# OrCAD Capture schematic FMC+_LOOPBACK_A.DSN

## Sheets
1 Title, Note, Block Diagram: title: FMC+ Loopback Card; rev: A1; note: 150-0330631-A1       (6XX-44455R)
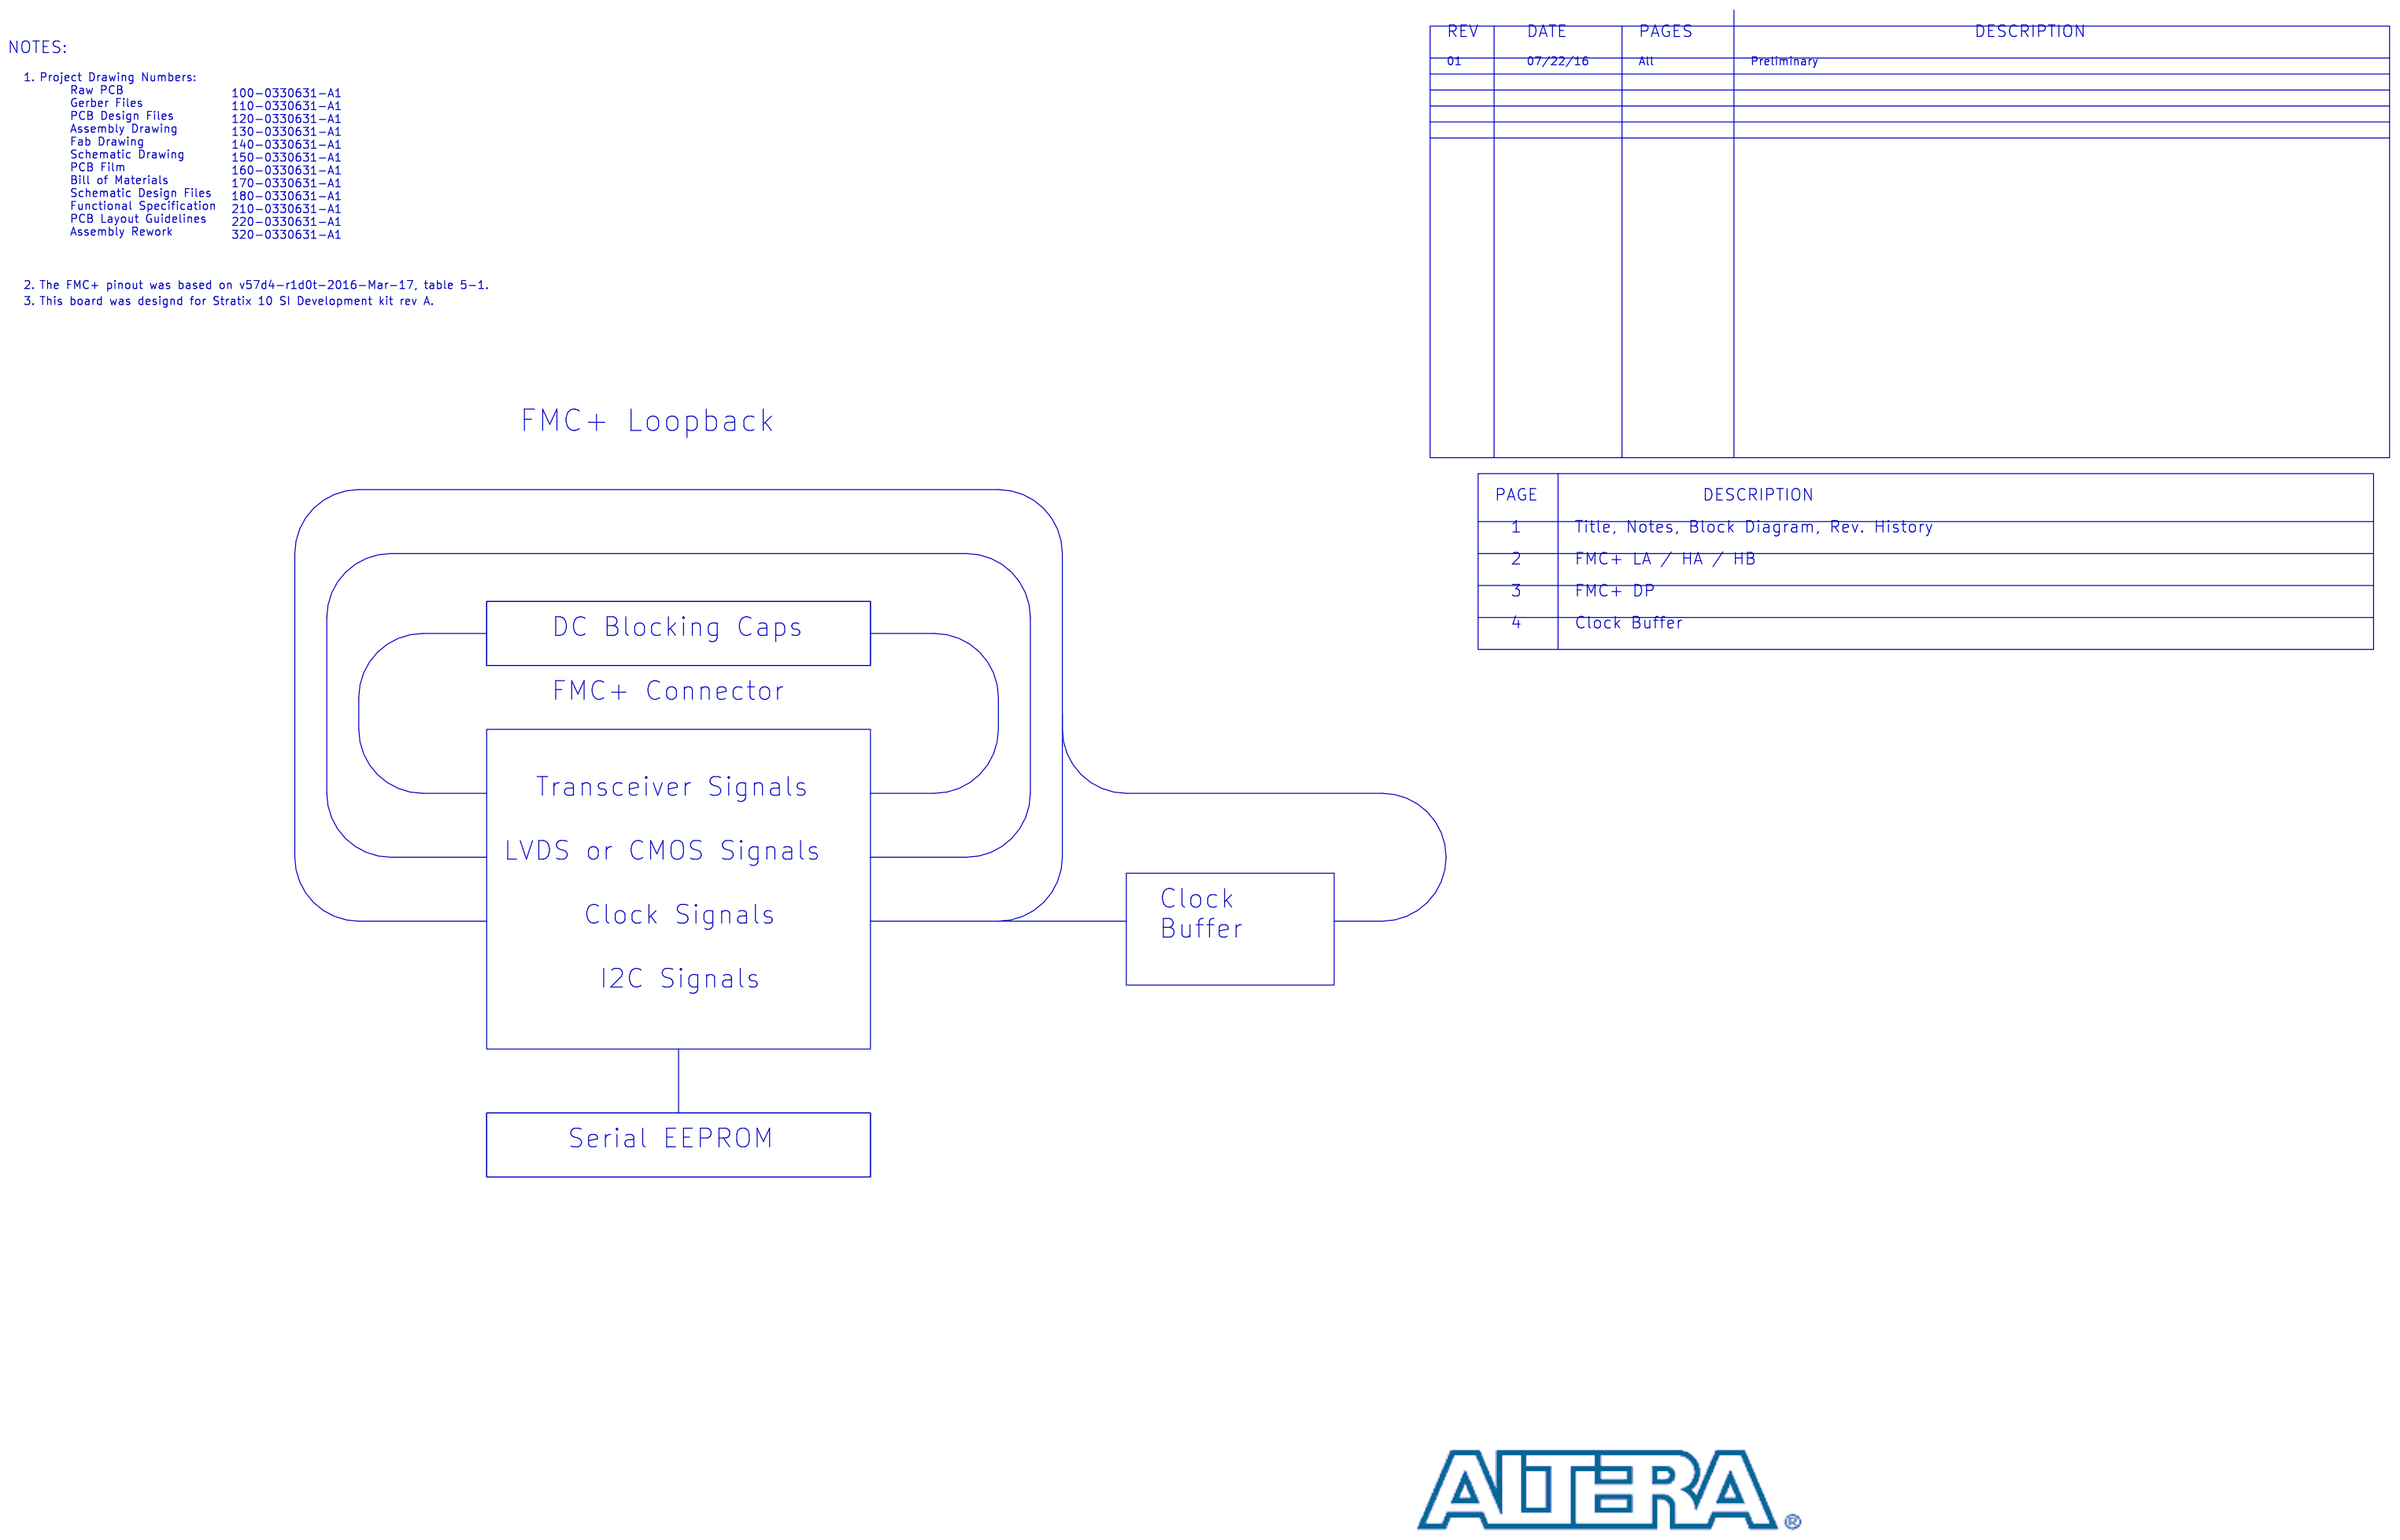
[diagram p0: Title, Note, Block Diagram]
2 FMC+ LA/HA/HB: size B
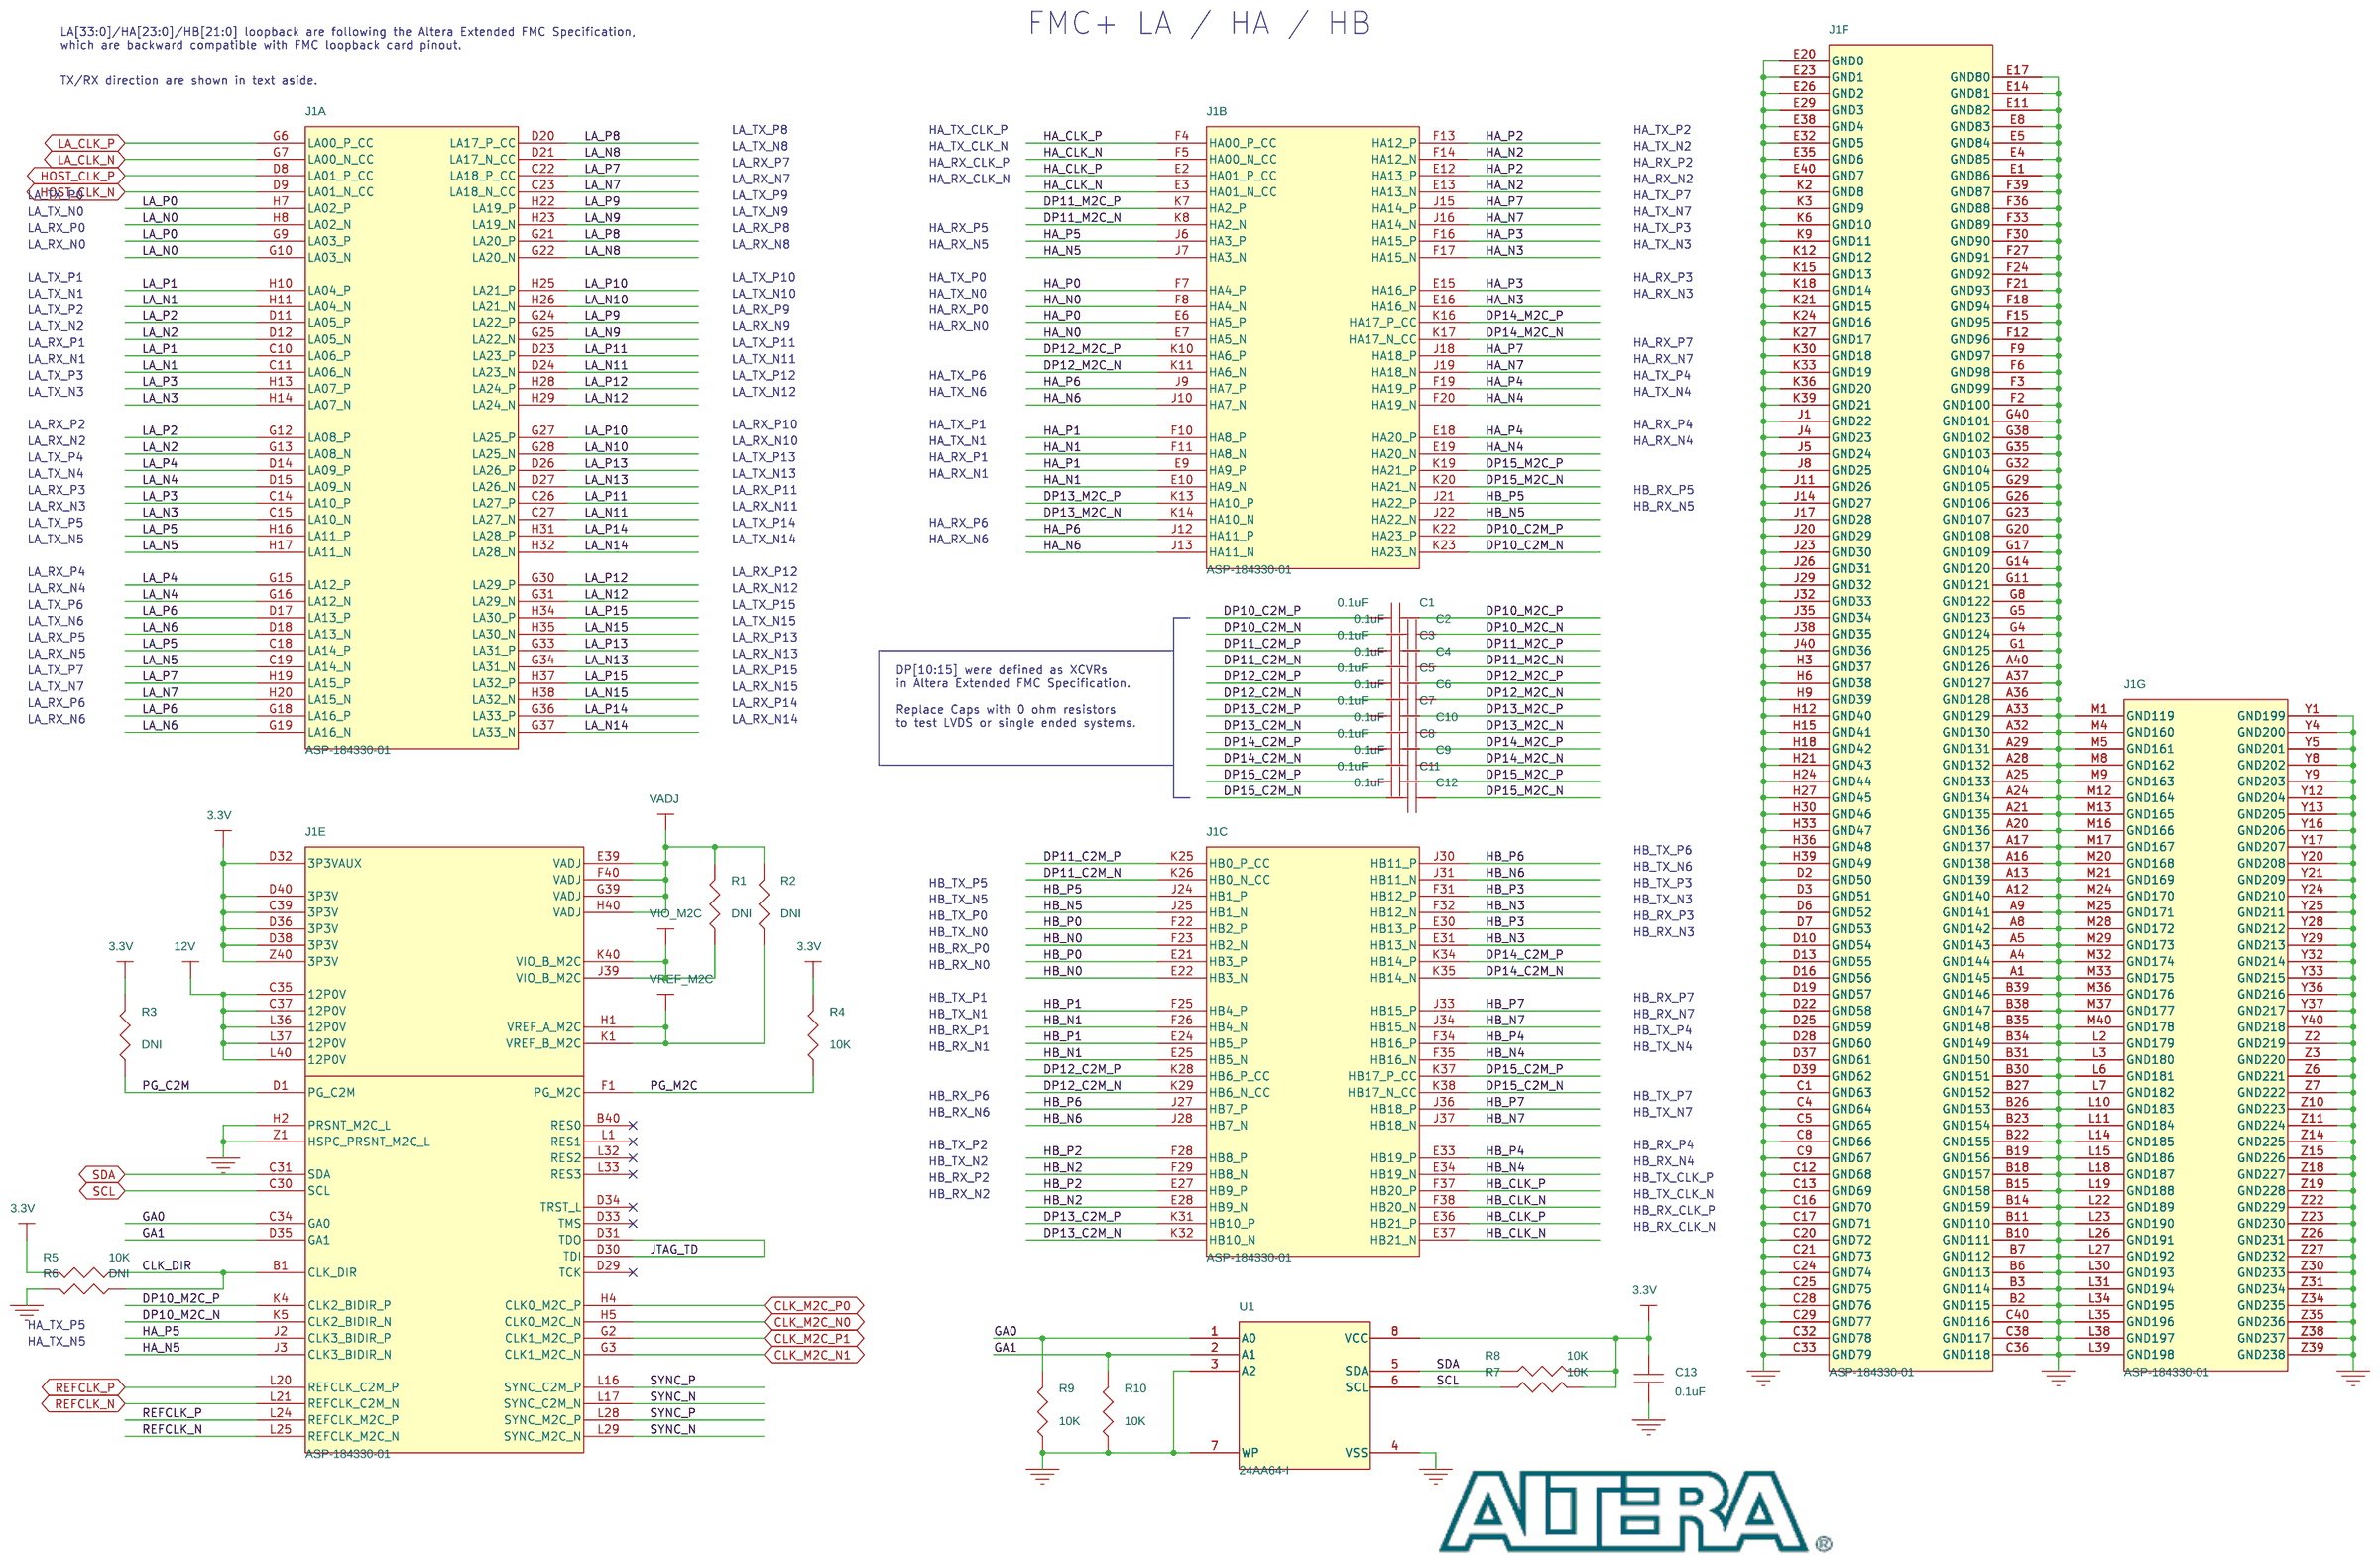
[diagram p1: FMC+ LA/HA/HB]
3 FMC+ DP: size B
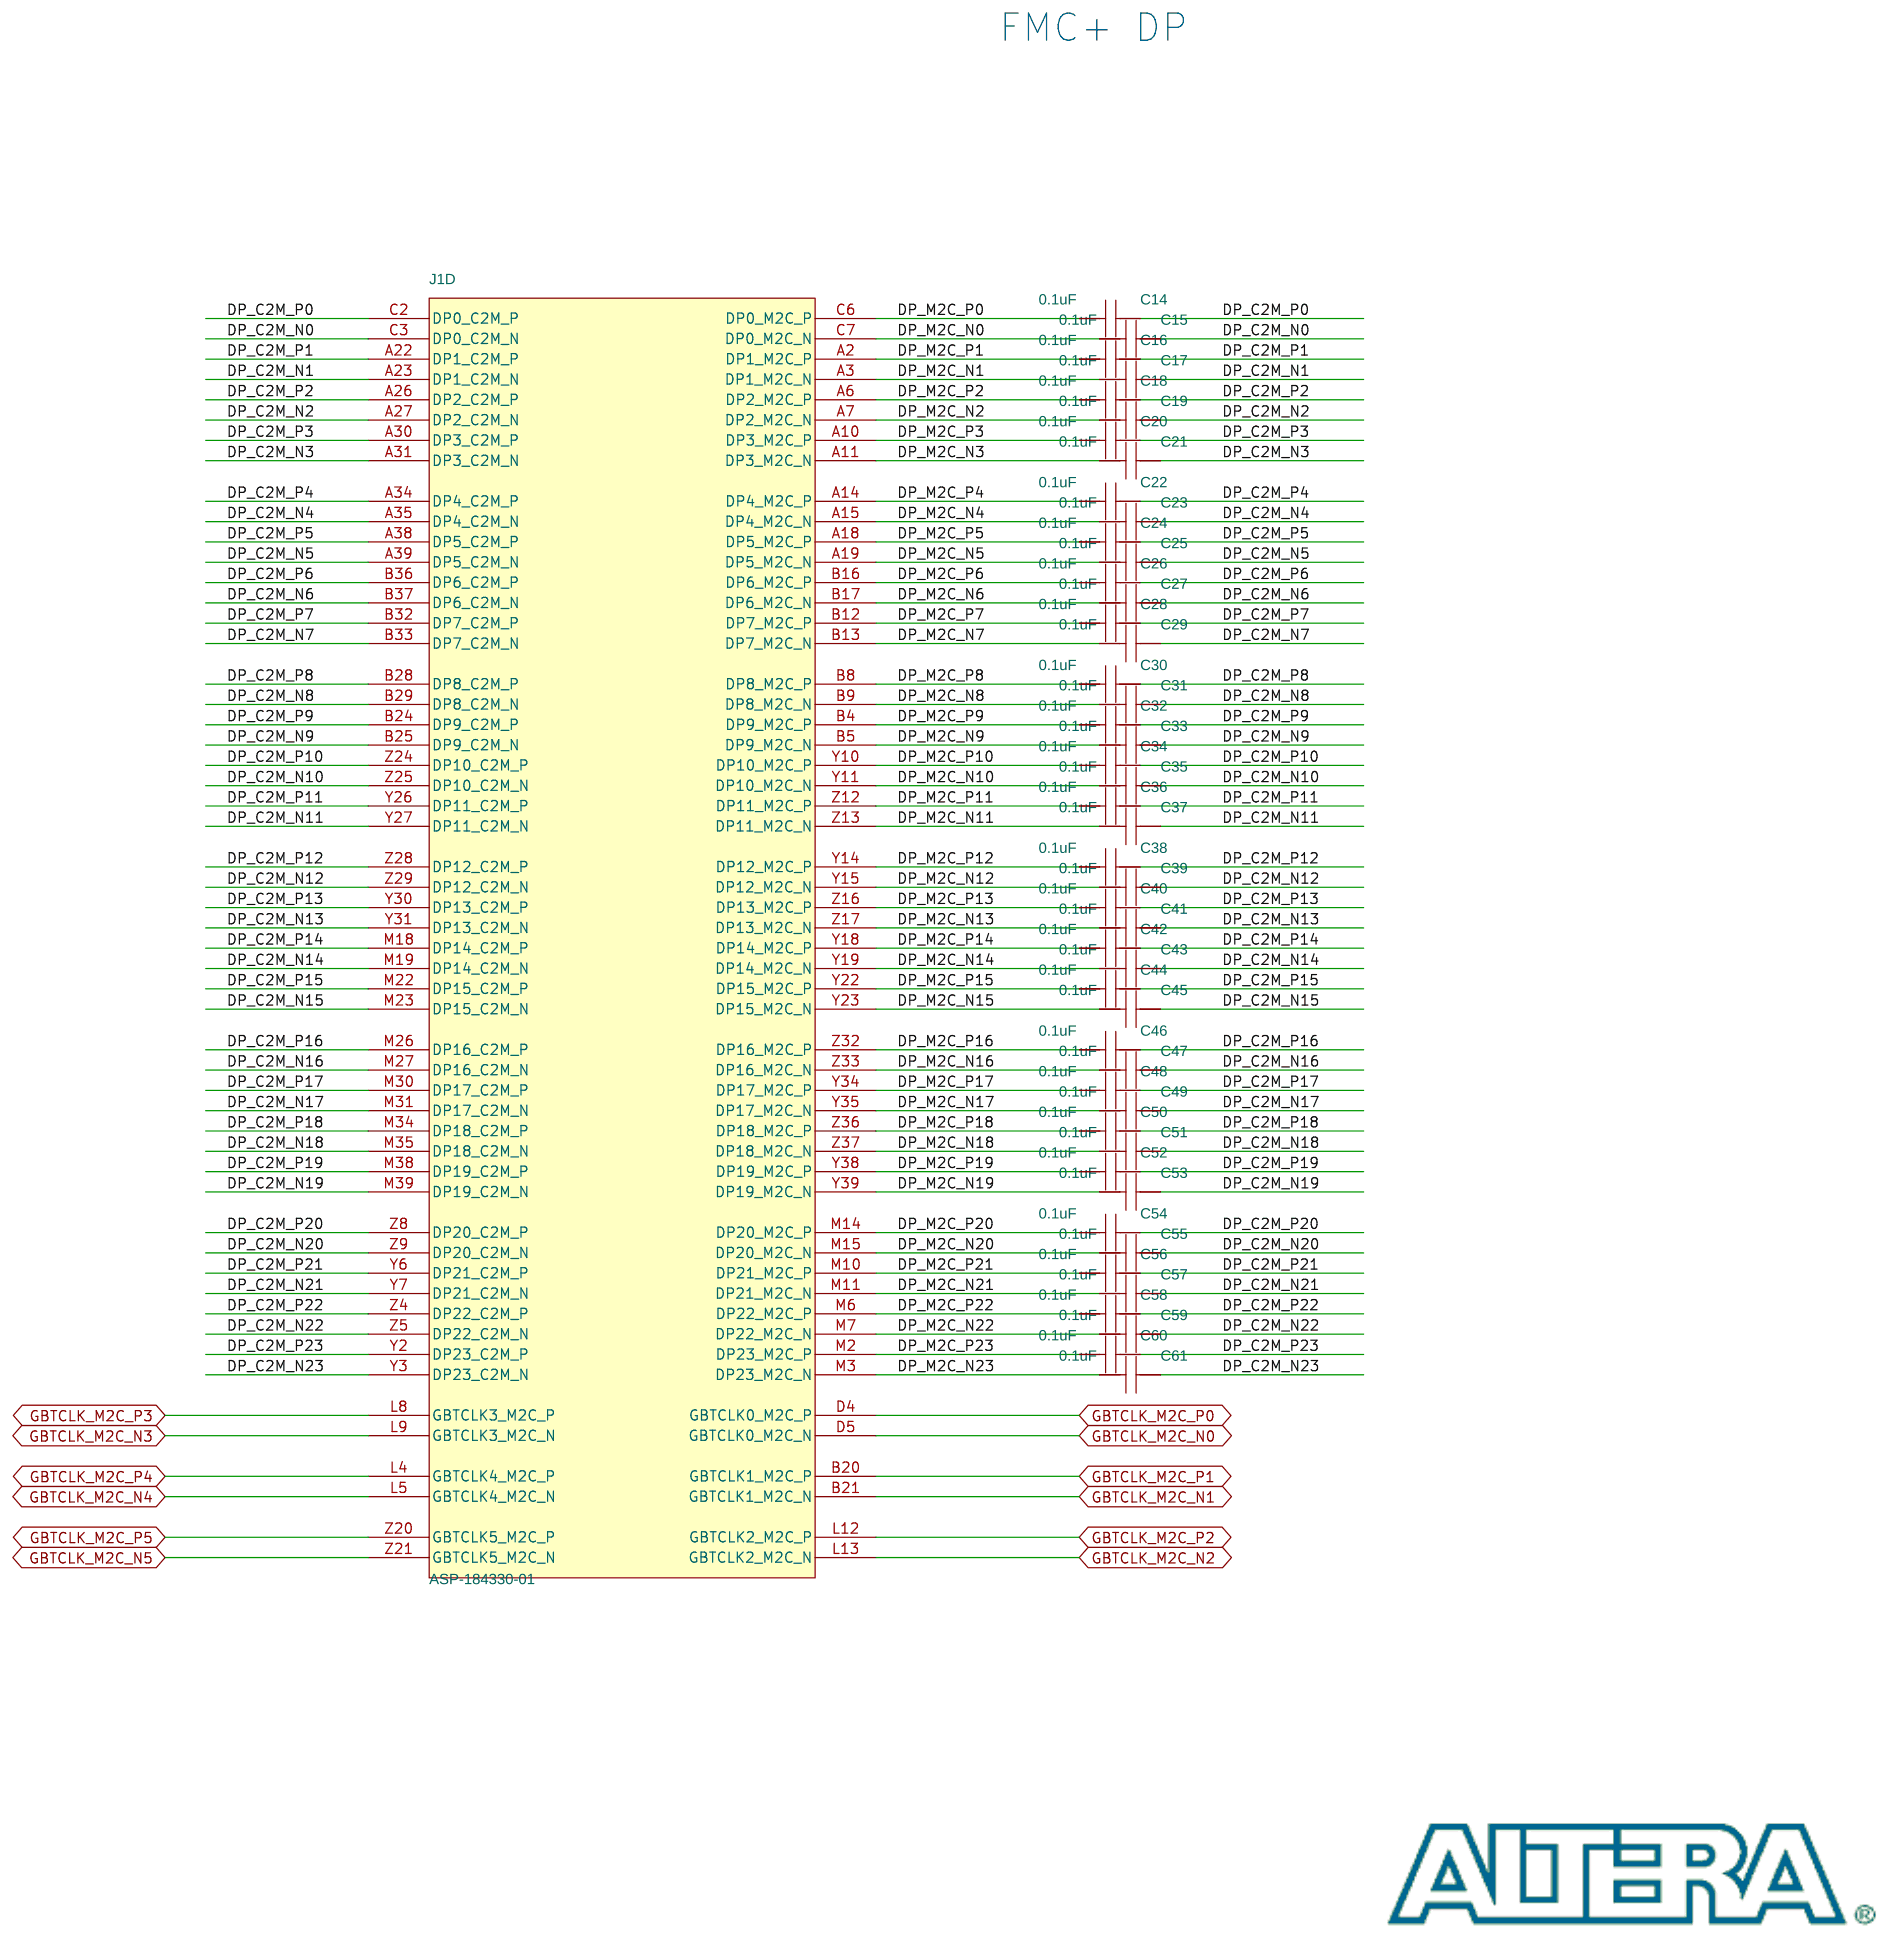
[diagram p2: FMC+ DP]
4 Clock Buffer: size B

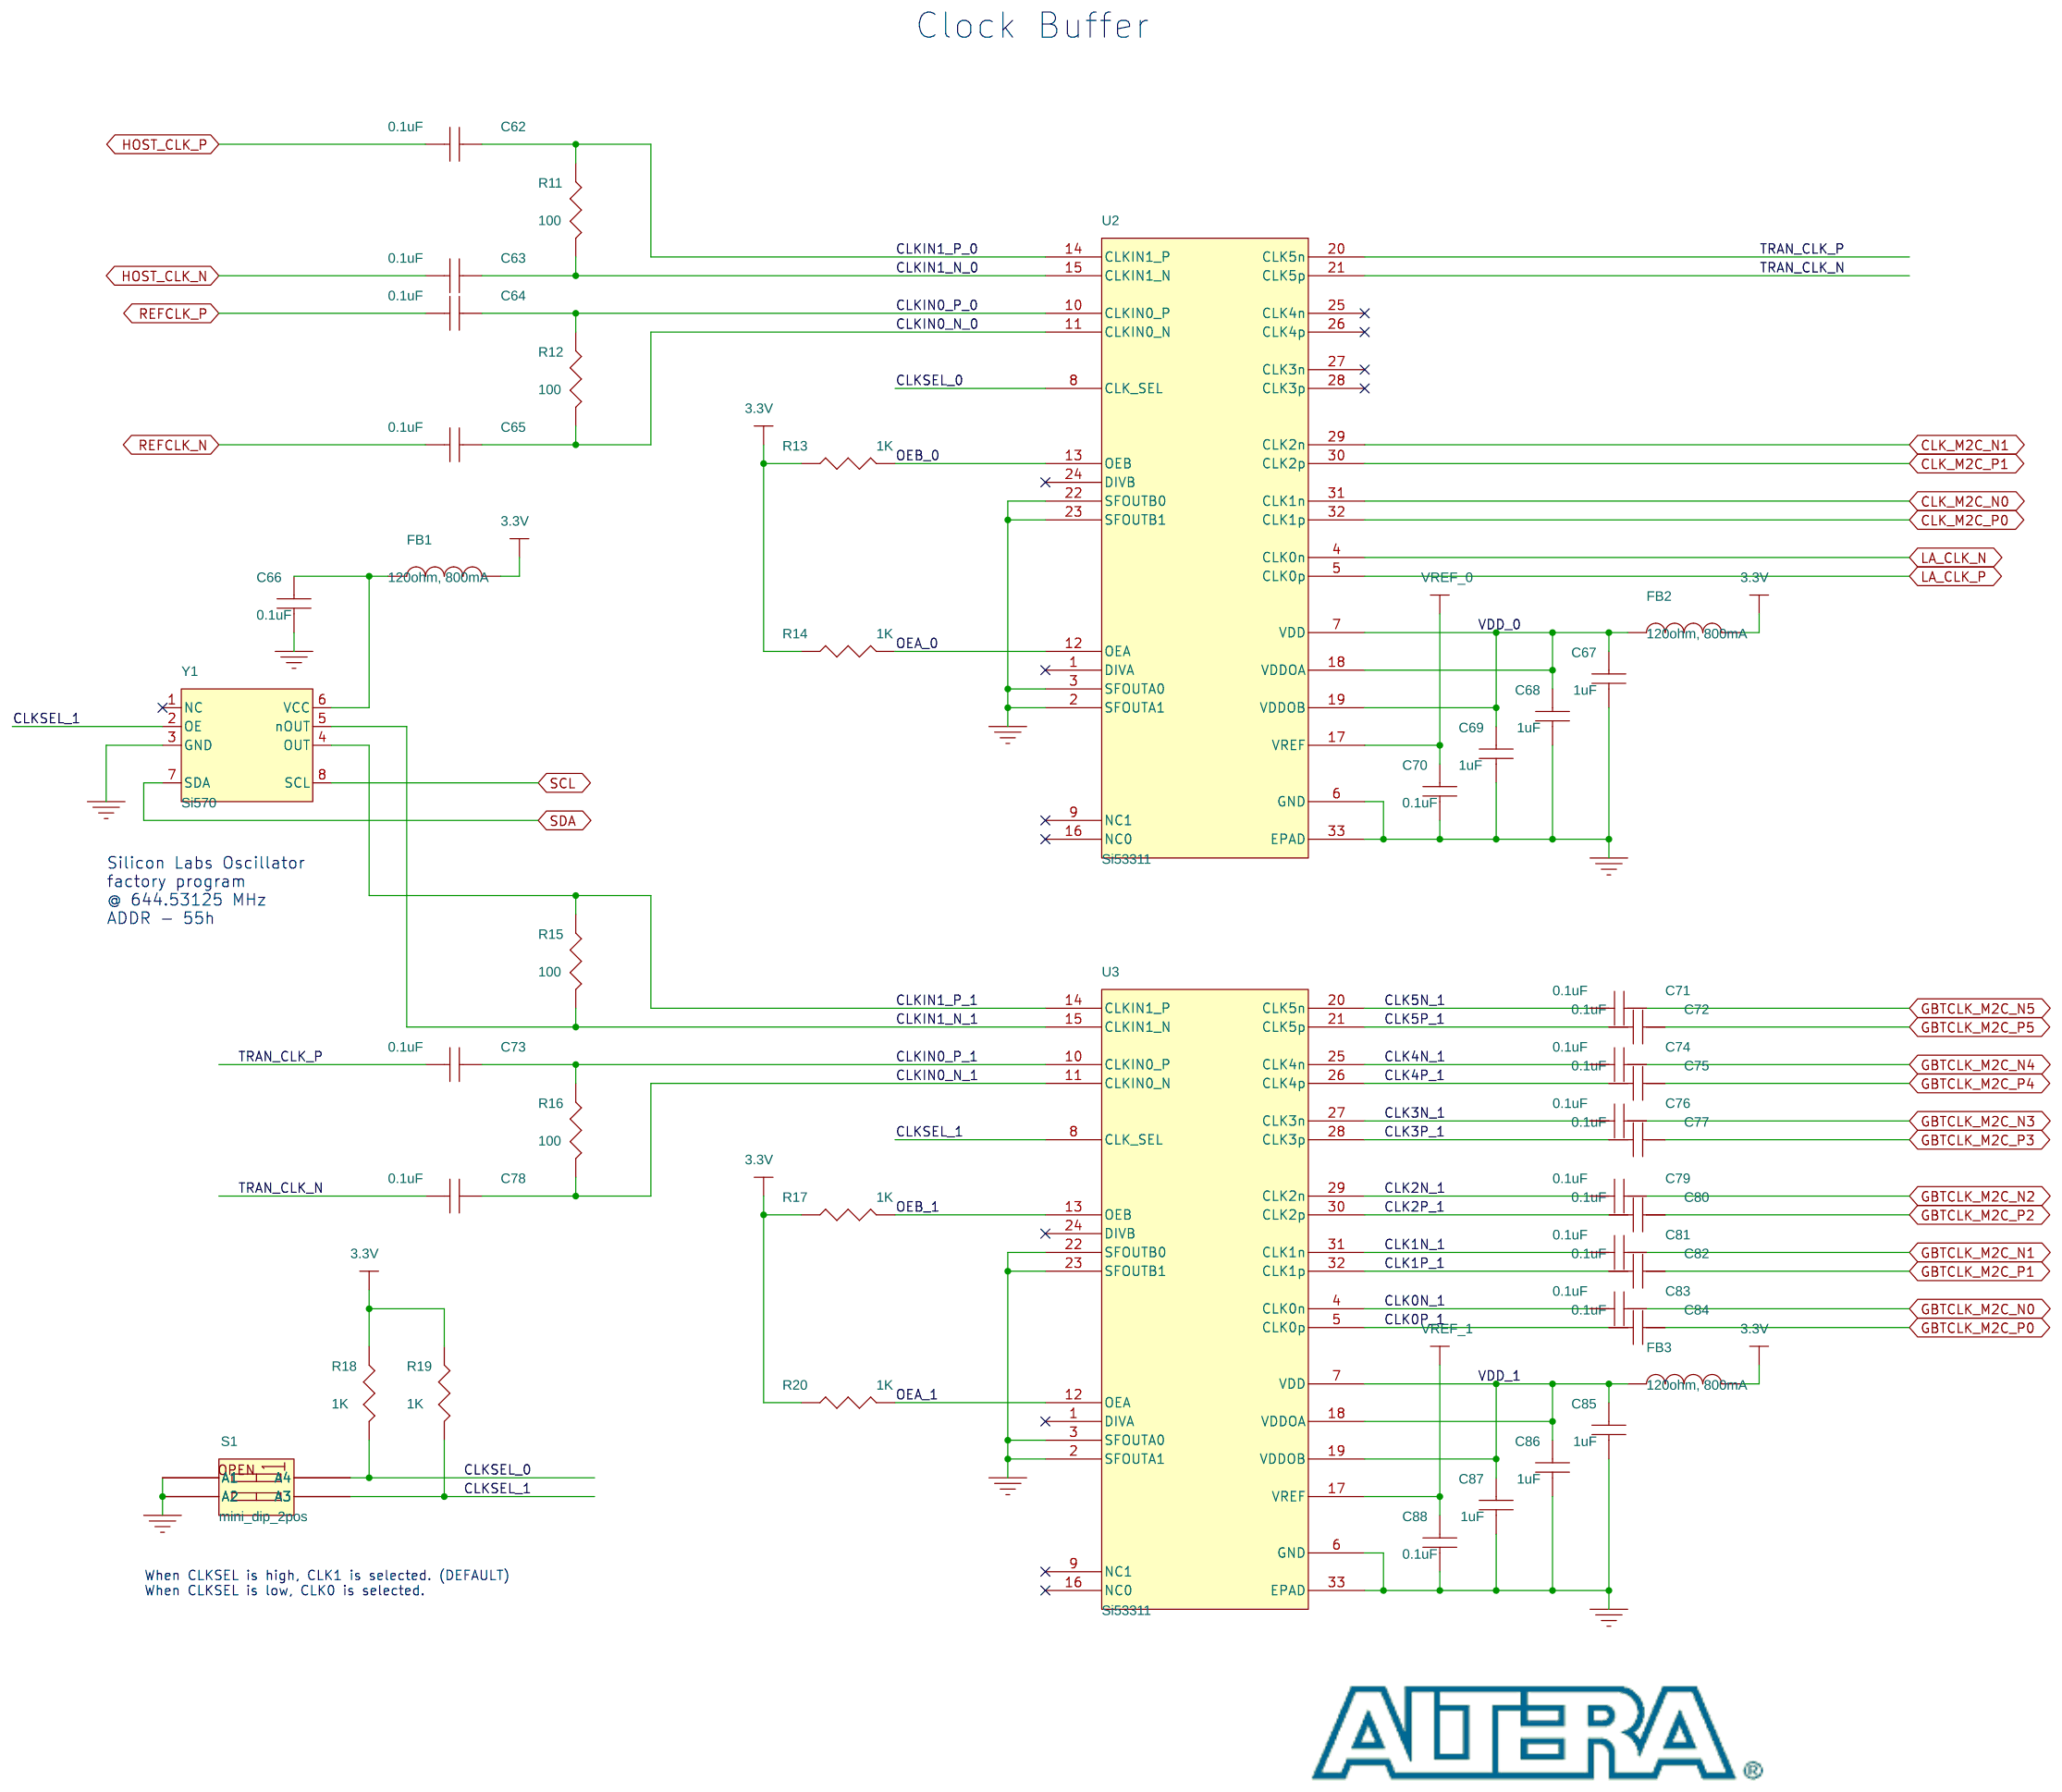
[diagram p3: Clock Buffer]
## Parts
sheet Clock Buffer
C62  0.1uF  [0402]
C63  0.1uF  [0402]
C64  0.1uF  [0402]
C65  0.1uF  [0402]
C66  0.1uF  [0402]
C67  1uF  [0603]
C68  1uF  [0603]
C69  1uF  [0603]
C70  0.1uF  [0402]
C71  0.1uF  [0402]
C72  0.1uF  [0402]
C73  0.1uF  [0402]
C74  0.1uF  [0402]
C75  0.1uF  [0402]
C76  0.1uF  [0402]
C77  0.1uF  [0402]
C78  0.1uF  [0402]
C79  0.1uF  [0402]
C80  0.1uF  [0402]
C81  0.1uF  [0402]
C82  0.1uF  [0402]
C83  0.1uF  [0402]
C84  0.1uF  [0402]
C85  1uF  [0603]
C86  1uF  [0603]
C87  1uF  [0603]
C88  0.1uF  [0402]
FB1  120ohm, 800mA  [805]
FB2  120ohm, 800mA  [805]
FB3  120ohm, 800mA  [805]
R11  100  [0402]
R12  100  [0402]
R13  1K  [0402]
R14  1K  [0402]
R15  100  [0402]
R16  100  [0402]
R17  1K  [0402]
R18  1K  [0402]
R19  1K  [0402]
R20  1K  [0402]
S1  mini_dip_2pos  [DIPSWITCH_SMT_2POS]
U2  Si53311  [QFN_32]
U3  Si53311  [QFN_32]
Y1  Si570  [OSC_SMD_8PIN_7X5]
sheet FMC+ DP
C14  0.1uF  [0201]
C15  0.1uF  [0201]
C16  0.1uF  [0201]
C17  0.1uF  [0201]
C18  0.1uF  [0201]
C19  0.1uF  [0201]
C20  0.1uF  [0201]
C21  0.1uF  [0201]
C22  0.1uF  [0201]
C23  0.1uF  [0201]
C24  0.1uF  [0201]
C25  0.1uF  [0201]
C26  0.1uF  [0201]
C27  0.1uF  [0201]
C28  0.1uF  [0201]
C29  0.1uF  [0201]
C30  0.1uF  [0201]
C31  0.1uF  [0201]
C32  0.1uF  [0201]
C33  0.1uF  [0201]
C34  0.1uF  [0201]
C35  0.1uF  [0201]
C36  0.1uF  [0201]
C37  0.1uF  [0201]
C38  0.1uF  [0201]
C39  0.1uF  [0201]
C40  0.1uF  [0201]
C41  0.1uF  [0201]
C42  0.1uF  [0201]
C43  0.1uF  [0201]
C44  0.1uF  [0201]
C45  0.1uF  [0201]
C46  0.1uF  [0201]
C47  0.1uF  [0201]
C48  0.1uF  [0201]
C49  0.1uF  [0201]
C50  0.1uF  [0201]
C51  0.1uF  [0201]
C52  0.1uF  [0201]
C53  0.1uF  [0201]
C54  0.1uF  [0201]
C55  0.1uF  [0201]
C56  0.1uF  [0201]
C57  0.1uF  [0201]
C58  0.1uF  [0201]
C59  0.1uF  [0201]
C60  0.1uF  [0201]
C61  0.1uF  [0201]
sheet FMC+ LA/HA/HB
C1  0.1uF  [0201]
C2  0.1uF  [0201]
C3  0.1uF  [0201]
C4  0.1uF  [0201]
C5  0.1uF  [0201]
C6  0.1uF  [0201]
C7  0.1uF  [0201]
C8  0.1uF  [0201]
C9  0.1uF  [0201]
C10  0.1uF  [0201]
C11  0.1uF  [0201]
C12  0.1uF  [0201]
C13  0.1uF  [0402]
J1  ASP-184330-01  [14x40_TERMINAL_Vita57p4]  (sections A,B,C,D,E,F,G)
R1  DNI  [0402]
R2  DNI  [0402]
R3  DNI  [0402]
R4  10K  [0402]
R5  10K  [0402]
R6  DNI  [0402]
R7  10K  [0402]
R8  10K  [0402]
R9  10K  [0402]
R10  10K  [0402]
U1  24AA64-I  [msop8]

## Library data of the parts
C13 C62-C66 C70-C84 C88 = CAP: CAP - CERAMIC,  0.1UF 0402 25VDC Y5V; AGILE_LINK: http://sj-agile9app/Agile/PLMServlet?action=OpenEmailObject&classid=10000&objid=213459527; Item Num: P03-15057R; LIFECYCLE_PHASE: Active; Lead Free Status: Lead Free; MFR_LIFECYCLE: Active; Manufacturer: Murata; Manufacturer Part Num: GRM155F51E104ZA01D; Num Pins: 2; PART_SUBCLASS: CAPACITORS; Part Class: CAPACITORS; RATED_VOLTAGE: 25V; RoHS Compliant: RoHS Compliant; SIGNAL_MODEL: DEFAULT_CAPACITOR_2.2e+06pF_2_1; TOLERANCE: +80%/-20%
C67-C69 C85-C87 = CAP: CAP - CERAMIC, 1.0UF, 10%, 6.3V, 0603, X5R; AGILE_LINK: http://sj-agile9app/Agile/PLMServlet?action=OpenEmailObject&classid=10000&objid=218158861; CAPACITANCE: 1.0uF; Item Num: P03-15095R; LIFECYCLE_PHASE: Active; MFR_LIFECYCLE: Active; Manufacturer: Panasonic; Manufacturer Part Num: ECJ-1VB0J105K; Num Pins: 2; PART_SUBCLASS: CAPACITORS; RATED_VOLTAGE: 6.3V; RoHS Compliant: RoHS Compliant; TOLERANCE: +/-10%
FB1-FB3 = INDUCTOR: FERRITE BEAD 800MA 120 OHM; Item Num: P04-16000R; Lead Free Status: No; Manufacturer: Steward; Manufacturer Part Num: LI0805H121R-10; Mfr Code: STED; Num Pins: 2; Part Class: Inductors; Price: 0.11; RoHS Compliant: Yes
R11 R12 R15 R16 = RESISTOR: RES,100 OHMS,1.0%,1/16W,0402; Item Num: P02-11381R; Lead Free Status: No; Manufacturer: Panasonic; Manufacturer Part Num: ERJ-2RKF1000X; Manufacturer's Part No.: ERJ-2RKF1000X; Num Pins: 2; Part Class: RESISTORS; Price: 0; RoHS Compliant: Yes
R13 R14 R17-R20 = R: RES - 1K OHM, 1/16W, 1%, 0402, SMD; Item Num: P02-14274R; Lead Free Status: Yes; Manufacturer: Vishay; Manufacturer Part Num: CRCW04021K00FKED; Num Pins: 2; Part Class: Resistors; Price: 0; RoHS Compliant: Yes
S1 = mini_dip_2pos: Item Num: P11-24530R
U2 U3 = Si53311_2: IC - 1:6 BUFFER/LEVEL TRANSLATOR WITH 2:1 INPUT MUX (<1.25GHZ), 32-QFN; Item Num: P01-17852R; Manufactuer Part Num: Si53311-B-GM; Manufacturer: Silicon Labs Inc.; Manufacturer Part Num: Si53311-B-GM
Y1 = OSC_Si570: OSC, SI570, 644.53125MHZ, I2C-PROGRAMMABLE, LVDS, 3.3V, +/-20PPM, ADDR=55H, 8PINS; Item Num: P13-27246R; Manufacturer Part Num: 570BCA000420DG
C1-C12 C14-C61 = CAP: CAP - 0.1UF 0201, 6.3V, 10% X5R; Dielectric: X5R; Item Num: P03-17603R; LIFECYCLE_PHASE: Active; Lead Free Status: Lead Free; Manufacturer: Murata; Manufacturer Part Num: GRM033R60J104KE19D; Num Pins: 2; Part Class: CAPACITORS; RoHS Compliant: RoHS Compliant; Tolerance: +/-10%
J1 = asp-184330-01: Manufacturer: Samtec
R1-R10 = RESISTOR: RES 10K OHM 1/16W 5% 0402 SMD; Item Num: P02-14023R; Lead Free Status: No; Manufacturer: Panasonic; Manufacturer Part Num: ERJ-2GEJ103X; Manufacturer's Part No.: ERJ-2GEJ103X; Num Pins: 2; Part Class: RESISTORS; Price: 0; RoHS Compliant: Yes; SIGNAL_MODEL: DEFAULT_RESISTOR_220OHM_2_1
U1 = 24AA64-I: IC - 64KBIT I2C SERIAL EEPROM; Item Num: P01-17386R; Manufacturer: Microchip Technology Inc.; Manufacturer Part Num: 24AA64-I/MS; Num Pins: 8; Part Class: ICS

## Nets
3.3V: C13.1 FB1.1 FB2.1 FB3.1 J1.C39(3P3V) J1.D32(3P3VAUX) J1.D36(3P3V) J1.D38(3P3V) J1.D40(3P3V) J1.Z40(3P3V) R3.1 R4.1 R5.1 R7.2 R8.2 R13.1 R14.1 R17.1 R18.1 R19.1 R20.1 U1.8(VCC)
12V: J1.C35(12P0V) J1.C37(12P0V) J1.L36(12P0V) J1.L37(12P0V) J1.L40(12P0V)
GND: C13.2 C66.2 C67.2 C68.2 C69.2 C70.2 C85.2 C86.2 C87.2 C88.2 J1.A1(GND145) J1.A4(GND144) J1.A5(GND143) J1.A8(GND142) J1.A9(GND141) J1.A12(GND140) J1.A13(GND139) J1.A16(GND138) J1.A17(GND137) J1.A20(GND136) J1.A21(GND135) J1.A24(GND134) J1.A25(GND133) J1.A28(GND132) J1.A29(GND131) J1.A32(GND130) J1.A33(GND129) J1.A36(GND128) J1.A37(GND127) J1.A40(GND126) J1.B2(GND115) J1.B3(GND114) J1.B6(GND113) J1.B7(GND112) J1.B10(GND111) J1.B11(GND110) J1.B14(GND159) J1.B15(GND158) J1.B18(GND157) J1.B19(GND156) J1.B22(GND155) J1.B23(GND154) J1.B26(GND153) J1.B27(GND152) J1.B30(GND151) J1.B31(GND150) J1.B34(GND149) J1.B35(GND148) J1.B38(GND147) J1.B39(GND146) J1.C1(GND63) J1.C4(GND64) J1.C5(GND65) J1.C8(GND66) J1.C9(GND67) J1.C12(GND68) J1.C13(GND69) J1.C16(GND70) J1.C17(GND71) J1.C20(GND72) J1.C21(GND73) J1.C24(GND74) J1.C25(GND75) J1.C28(GND76) J1.C29(GND77) J1.C32(GND78) J1.C33(GND79) J1.C36(GND118) J1.C38(GND117) J1.C40(GND116) J1.D2(GND50) J1.D3(GND51) J1.D6(GND52) J1.D7(GND53) J1.D10(GND54) J1.D13(GND55) J1.D16(GND56) J1.D19(GND57) J1.D22(GND58) J1.D25(GND59) J1.D28(GND60) J1.D37(GND61) J1.D39(GND62) J1.E1(GND86) J1.E4(GND85) J1.E5(GND84) J1.E8(GND83) J1.E11(GND82) J1.E14(GND81) J1.E17(GND80) J1.E20(GND0) J1.E23(GND1) J1.E26(GND2) J1.E29(GND3) J1.E32(GND5) J1.E35(GND6) J1.E38(GND4) J1.E40(GND7) J1.F2(GND100) J1.F3(GND99) J1.F6(GND98) J1.F9(GND97) J1.F12(GND96) J1.F15(GND95) J1.F18(GND94) J1.F21(GND93) J1.F24(GND92) J1.F27(GND91) J1.F30(GND90) J1.F33(GND89) J1.F36(GND88) J1.F39(GND87) J1.G1(GND125) J1.G4(GND124) J1.G5(GND123) J1.G8(GND122) J1.G11(GND121) J1.G14(GND120) J1.G17(GND109) J1.G20(GND108) J1.G23(GND107) J1.G26(GND106) J1.G29(GND105) J1.G32(GND104) J1.G35(GND103) J1.G38(GND102) J1.G40(GND101) J1.H2(PRSNT_M2C_L) J1.H3(GND37) J1.H6(GND38) J1.H9(GND39) J1.H12(GND40) J1.H15(GND41) J1.H18(GND42) J1.H21(GND43) J1.H24(GND44) J1.H27(GND45) J1.H30(GND46) J1.H33(GND47) J1.H36(GND48) J1.H39(GND49) J1.J1(GND22) J1.J4(GND23) J1.J5(GND24) J1.J8(GND25) J1.J11(GND26) J1.J14(GND27) J1.J17(GND28) J1.J20(GND29) J1.J23(GND30) J1.J26(GND31) J1.J29(GND32) J1.J32(GND33) J1.J35(GND34) J1.J38(GND35) J1.J40(GND36) J1.K2(GND8) J1.K3(GND9) J1.K6(GND10) J1.K9(GND11) J1.K12(GND12) J1.K15(GND13) J1.K18(GND14) J1.K21(GND15) J1.K24(GND16) J1.K27(GND17) J1.K30(GND18) J1.K33(GND19) J1.K36(GND20) J1.K39(GND21) J1.L2(GND179) J1.L3(GND180) J1.L6(GND181) J1.L7(GND182) J1.L10(GND183) J1.L11(GND184) J1.L14(GND185) J1.L15(GND186) J1.L18(GND187) J1.L19(GND188) J1.L22(GND189) J1.L23(GND190) J1.L26(GND191) J1.L27(GND192) J1.L30(GND193) J1.L31(GND194) J1.L34(GND195) J1.L35(GND196) J1.L38(GND197) J1.L39(GND198) J1.M1(GND119) J1.M4(GND160) J1.M5(GND161) J1.M8(GND162) J1.M9(GND163) J1.M12(GND164) J1.M13(GND165) J1.M16(GND166) J1.M17(GND167) J1.M20(GND168) J1.M21(GND169) J1.M24(GND170) J1.M25(GND171) J1.M28(GND172) J1.M29(GND173) J1.M32(GND174) J1.M33(GND175) J1.M36(GND176) J1.M37(GND177) J1.M40(GND178) J1.Y1(GND199) J1.Y4(GND200) J1.Y5(GND201) J1.Y8(GND202) J1.Y9(GND203) J1.Y12(GND204) J1.Y13(GND205) J1.Y16(GND206) J1.Y17(GND207) J1.Y20(GND208) J1.Y21(GND209) J1.Y24(GND210) J1.Y25(GND211) J1.Y28(GND212) J1.Y29(GND213) J1.Y32(GND214) J1.Y33(GND215) J1.Y36(GND216) J1.Y37(GND217) J1.Y40(GND218) J1.Z1(HSPC_PRSNT_M2C_L) J1.Z2(GND219) J1.Z3(GND220) J1.Z6(GND221) J1.Z7(GND222) J1.Z10(GND223) J1.Z11(GND224) J1.Z14(GND225) J1.Z15(GND226) J1.Z18(GND227) J1.Z19(GND228) J1.Z22(GND229) J1.Z23(GND230) J1.Z26(GND231) J1.Z27(GND232) J1.Z30(GND233) J1.Z31(GND234) J1.Z34(GND235) J1.Z35(GND236) J1.Z38(GND237) J1.Z39(GND238) R6.1 R9.1 R10.1 S1.1(A1) S1.2(A2) U1.3(A2) U1.4(VSS) U1.7(WP) U2.2(SFOUTA1) U2.3(SFOUTA0) U2.6(GND) U2.22(SFOUTB0) U2.23(SFOUTB1) U2.33(EPAD) U3.2(SFOUTA1) U3.3(SFOUTA0) U3.6(GND) U3.22(SFOUTB0) U3.23(SFOUTB1) U3.33(EPAD) Y1.3(GND)
VDD_0: C67.1 C68.1 C69.1 FB2.2 U2.7(VDD) U2.18(VDDOA) U2.19(VDDOB)
VDD_1: C85.1 C86.1 C87.1 FB3.2 U3.7(VDD) U3.18(VDDOA) U3.19(VDDOB)
CLK0N_1: C83.2 U3.4(CLK0n)
CLK0P_1: C84.2 U3.5(CLK0p)
CLK1N_1: C81.2 U3.31(CLK1n)
CLK1P_1: C82.2 U3.32(CLK1p)
CLK2N_1: C79.2 U3.29(CLK2n)
CLK2P_1: C80.2 U3.30(CLK2p)
CLK3N_1: C76.2 U3.27(CLK3n)
CLK3P_1: C77.2 U3.28(CLK3p)
CLK4N_1: C74.2 U3.25(CLK4n)
CLK4P_1: C75.2 U3.26(CLK4p)
CLK5N_1: C71.2 U3.20(CLK5n)
CLK5P_1: C72.2 U3.21(CLK5p)
CLK_DIR: J1.B1(CLK_DIR) R5.2 R6.2
CLK_M2C_N0: J1.H5(CLK0_M2C_N) U2.31(CLK1n)
CLK_M2C_N1: J1.G3(CLK1_M2C_N) U2.29(CLK2n)
CLK_M2C_P0: J1.H4(CLK0_M2C_P) U2.32(CLK1p)
CLK_M2C_P1: J1.G2(CLK1_M2C_P) U2.30(CLK2p)
CLKIN0_N_0: C65.1 R12.2 U2.11(CLKIN0_N)
CLKIN0_N_1: C78.1 R16.2 U3.11(CLKIN0_N)
CLKIN0_P_0: C64.1 R12.1 U2.10(CLKIN0_P)
CLKIN0_P_1: C73.1 R16.1 U3.10(CLKIN0_P)
CLKIN1_N_0: C63.1 R11.2 U2.15(CLKIN1_N)
CLKIN1_N_1: R15.2 U3.15(CLKIN1_N) Y1.5(nOUT)
CLKIN1_P_0: C62.1 R11.1 U2.14(CLKIN1_P)
CLKIN1_P_1: R15.1 U3.14(CLKIN1_P) Y1.4(OUT)
CLKSEL_0: R18.2 S1.4(A4) U2.8(CLK_SEL)
CLKSEL_1: R19.2 S1.3(A3) U3.8(CLK_SEL) Y1.2(OE)
DP10_C2M_N: C2.2 J1.K23(HA23_N)
DP10_C2M_P: C1.2 J1.K22(HA23_P)
DP10_M2C_N: C2.1 J1.K5(CLK2_BIDIR_N)
DP10_M2C_P: C1.1 J1.K4(CLK2_BIDIR_P)
DP11_C2M_N: C4.2 J1.K26(HB0_N_CC)
DP11_C2M_P: C3.2 J1.K25(HB0_P_CC)
DP11_M2C_N: C4.1 J1.K8(HA2_N)
DP11_M2C_P: C3.1 J1.K7(HA2_P)
DP12_C2M_N: C6.2 J1.K29(HB6_N_CC)
DP12_C2M_P: C5.2 J1.K28(HB6_P_CC)
DP12_M2C_N: C6.1 J1.K11(HA6_N)
DP12_M2C_P: C5.1 J1.K10(HA6_P)
DP13_C2M_N: C10.2 J1.K32(HB10_N)
DP13_C2M_P: C7.2 J1.K31(HB10_P)
DP13_M2C_N: C10.1 J1.K14(HA10_N)
DP13_M2C_P: C7.1 J1.K13(HA10_P)
DP14_C2M_N: C9.2 J1.K35(HB14_N)
DP14_C2M_P: C8.2 J1.K34(HB14_P)
DP14_M2C_N: C9.1 J1.K17(HA17_N_CC)
DP14_M2C_P: C8.1 J1.K16(HA17_P_CC)
DP15_C2M_N: C12.2 J1.K38(HB17_N_CC)
DP15_C2M_P: C11.2 J1.K37(HB17_P_CC)
DP15_M2C_N: C12.1 J1.K20(HA21_N)
DP15_M2C_P: C11.1 J1.K19(HA21_P)
DP_C2M_N0: C15.1 J1.C3(DP0_C2M_N)
DP_C2M_N1: C17.1 J1.A23(DP1_C2M_N)
DP_C2M_N2: C19.1 J1.A27(DP2_C2M_N)
DP_C2M_N3: C21.1 J1.A31(DP3_C2M_N)
DP_C2M_N4: C23.1 J1.A35(DP4_C2M_N)
DP_C2M_N5: C25.1 J1.A39(DP5_C2M_N)
DP_C2M_N6: C27.1 J1.B37(DP6_C2M_N)
DP_C2M_N7: C29.1 J1.B33(DP7_C2M_N)
DP_C2M_N8: C31.1 J1.B29(DP8_C2M_N)
DP_C2M_N9: C33.1 J1.B25(DP9_C2M_N)
DP_C2M_N10: C35.1 J1.Z25(DP10_C2M_N)
DP_C2M_N11: C37.1 J1.Y27(DP11_C2M_N)
DP_C2M_N12: C39.1 J1.Z29(DP12_C2M_N)
DP_C2M_N13: C41.1 J1.Y31(DP13_C2M_N)
DP_C2M_N14: C43.1 J1.M19(DP14_C2M_N)
DP_C2M_N15: C45.1 J1.M23(DP15_C2M_N)
DP_C2M_N16: C47.1 J1.M27(DP16_C2M_N)
DP_C2M_N17: C49.1 J1.M31(DP17_C2M_N)
DP_C2M_N18: C51.1 J1.M35(DP18_C2M_N)
DP_C2M_N19: C53.1 J1.M39(DP19_C2M_N)
DP_C2M_N20: C55.1 J1.Z9(DP20_C2M_N)
DP_C2M_N21: C57.1 J1.Y7(DP21_C2M_N)
DP_C2M_N22: C59.1 J1.Z5(DP22_C2M_N)
DP_C2M_N23: C61.1 J1.Y3(DP23_C2M_N)
DP_C2M_P0: C14.1 J1.C2(DP0_C2M_P)
DP_C2M_P1: C16.1 J1.A22(DP1_C2M_P)
DP_C2M_P2: C18.1 J1.A26(DP2_C2M_P)
DP_C2M_P3: C20.1 J1.A30(DP3_C2M_P)
DP_C2M_P4: C22.1 J1.A34(DP4_C2M_P)
DP_C2M_P5: C24.1 J1.A38(DP5_C2M_P)
DP_C2M_P6: C26.1 J1.B36(DP6_C2M_P)
DP_C2M_P7: C28.1 J1.B32(DP7_C2M_P)
DP_C2M_P8: C30.1 J1.B28(DP8_C2M_P)
DP_C2M_P9: C32.1 J1.B24(DP9_C2M_P)
DP_C2M_P10: C34.1 J1.Z24(DP10_C2M_P)
DP_C2M_P11: C36.1 J1.Y26(DP11_C2M_P)
DP_C2M_P12: C38.1 J1.Z28(DP12_C2M_P)
DP_C2M_P13: C40.1 J1.Y30(DP13_C2M_P)
DP_C2M_P14: C42.1 J1.M18(DP14_C2M_P)
DP_C2M_P15: C44.1 J1.M22(DP15_C2M_P)
DP_C2M_P16: C46.1 J1.M26(DP16_C2M_P)
DP_C2M_P17: C48.1 J1.M30(DP17_C2M_P)
DP_C2M_P18: C50.1 J1.M34(DP18_C2M_P)
DP_C2M_P19: C52.1 J1.M38(DP19_C2M_P)
DP_C2M_P20: C54.1 J1.Z8(DP20_C2M_P)
DP_C2M_P21: C56.1 J1.Y6(DP21_C2M_P)
DP_C2M_P22: C58.1 J1.Z4(DP22_C2M_P)
DP_C2M_P23: C60.1 J1.Y2(DP23_C2M_P)
DP_M2C_N0: C15.2 J1.C7(DP0_M2C_N)
DP_M2C_N1: C17.2 J1.A3(DP1_M2C_N)
DP_M2C_N2: C19.2 J1.A7(DP2_M2C_N)
DP_M2C_N3: C21.2 J1.A11(DP3_M2C_N)
DP_M2C_N4: C23.2 J1.A15(DP4_M2C_N)
DP_M2C_N5: C25.2 J1.A19(DP5_M2C_N)
DP_M2C_N6: C27.2 J1.B17(DP6_M2C_N)
DP_M2C_N7: C29.2 J1.B13(DP7_M2C_N)
DP_M2C_N8: C31.2 J1.B9(DP8_M2C_N)
DP_M2C_N9: C33.2 J1.B5(DP9_M2C_N)
DP_M2C_N10: C35.2 J1.Y11(DP10_M2C_N)
DP_M2C_N11: C37.2 J1.Z13(DP11_M2C_N)
DP_M2C_N12: C39.2 J1.Y15(DP12_M2C_N)
DP_M2C_N13: C41.2 J1.Z17(DP13_M2C_N)
DP_M2C_N14: C43.2 J1.Y19(DP14_M2C_N)
DP_M2C_N15: C45.2 J1.Y23(DP15_M2C_N)
DP_M2C_N16: C47.2 J1.Z33(DP16_M2C_N)
DP_M2C_N17: C49.2 J1.Y35(DP17_M2C_N)
DP_M2C_N18: C51.2 J1.Z37(DP18_M2C_N)
DP_M2C_N19: C53.2 J1.Y39(DP19_M2C_N)
DP_M2C_N20: C55.2 J1.M15(DP20_M2C_N)
DP_M2C_N21: C57.2 J1.M11(DP21_M2C_N)
DP_M2C_N22: C59.2 J1.M7(DP22_M2C_N)
DP_M2C_N23: C61.2 J1.M3(DP23_M2C_N)
DP_M2C_P0: C14.2 J1.C6(DP0_M2C_P)
DP_M2C_P1: C16.2 J1.A2(DP1_M2C_P)
DP_M2C_P2: C18.2 J1.A6(DP2_M2C_P)
DP_M2C_P3: C20.2 J1.A10(DP3_M2C_P)
DP_M2C_P4: C22.2 J1.A14(DP4_M2C_P)
DP_M2C_P5: C24.2 J1.A18(DP5_M2C_P)
DP_M2C_P6: C26.2 J1.B16(DP6_M2C_P)
DP_M2C_P7: C28.2 J1.B12(DP7_M2C_P)
DP_M2C_P8: C30.2 J1.B8(DP8_M2C_P)
DP_M2C_P9: C32.2 J1.B4(DP9_M2C_P)
DP_M2C_P10: C34.2 J1.Y10(DP10_M2C_P)
DP_M2C_P11: C36.2 J1.Z12(DP11_M2C_P)
DP_M2C_P12: C38.2 J1.Y14(DP12_M2C_P)
DP_M2C_P13: C40.2 J1.Z16(DP13_M2C_P)
DP_M2C_P14: C42.2 J1.Y18(DP14_M2C_P)
DP_M2C_P15: C44.2 J1.Y22(DP15_M2C_P)
DP_M2C_P16: C46.2 J1.Z32(DP16_M2C_P)
DP_M2C_P17: C48.2 J1.Y34(DP17_M2C_P)
DP_M2C_P18: C50.2 J1.Z36(DP18_M2C_P)
DP_M2C_P19: C52.2 J1.Y38(DP19_M2C_P)
DP_M2C_P20: C54.2 J1.M14(DP20_M2C_P)
DP_M2C_P21: C56.2 J1.M10(DP21_M2C_P)
DP_M2C_P22: C58.2 J1.M6(DP22_M2C_P)
DP_M2C_P23: C60.2 J1.M2(DP23_M2C_P)
GA0: J1.C34(GA0) R9.2 U1.1(A0)
GA1: J1.D35(GA1) R10.2 U1.2(A1)
GBTCLK_M2C_N0: C83.1 J1.D5(GBTCLK0_M2C_N)
GBTCLK_M2C_N1: C81.1 J1.B21(GBTCLK1_M2C_N)
GBTCLK_M2C_N2: C79.1 J1.L13(GBTCLK2_M2C_N)
GBTCLK_M2C_N3: C76.1 J1.L9(GBTCLK3_M2C_N)
GBTCLK_M2C_N4: C74.1 J1.L5(GBTCLK4_M2C_N)
GBTCLK_M2C_N5: C71.1 J1.Z21(GBTCLK5_M2C_N)
GBTCLK_M2C_P0: C84.1 J1.D4(GBTCLK0_M2C_P)
GBTCLK_M2C_P1: C82.1 J1.B20(GBTCLK1_M2C_P)
GBTCLK_M2C_P2: C80.1 J1.L12(GBTCLK2_M2C_P)
GBTCLK_M2C_P3: C77.1 J1.L8(GBTCLK3_M2C_P)
GBTCLK_M2C_P4: C75.1 J1.L4(GBTCLK4_M2C_P)
GBTCLK_M2C_P5: C72.1 J1.Z20(GBTCLK5_M2C_P)
HA_CLK_N: J1.E3(HA01_N_CC) J1.F5(HA00_N_CC)
HA_CLK_P: J1.E2(HA01_P_CC) J1.F4(HA00_P_CC)
HA_N0: J1.E7(HA5_N) J1.F8(HA4_N)
HA_N1: J1.E10(HA9_N) J1.F11(HA8_N)
HA_N2: J1.E13(HA13_N) J1.F14(HA12_N)
HA_N3: J1.E16(HA16_N) J1.F17(HA15_N)
HA_N4: J1.E19(HA20_N) J1.F20(HA19_N)
HA_N5: J1.J3(CLK3_BIDIR_N) J1.J7(HA3_N)
HA_N6: J1.J10(HA7_N) J1.J13(HA11_N)
HA_N7: J1.J16(HA14_N) J1.J19(HA18_N)
HA_P0: J1.E6(HA5_P) J1.F7(HA4_P)
HA_P1: J1.E9(HA9_P) J1.F10(HA8_P)
HA_P2: J1.E12(HA13_P) J1.F13(HA12_P)
HA_P3: J1.E15(HA16_P) J1.F16(HA15_P)
HA_P4: J1.E18(HA20_P) J1.F19(HA19_P)
HA_P5: J1.J2(CLK3_BIDIR_P) J1.J6(HA3_P)
HA_P6: J1.J9(HA7_P) J1.J12(HA11_P)
HA_P7: J1.J15(HA14_P) J1.J18(HA18_P)
HB_CLK_N: J1.E37(HB21_N) J1.F38(HB20_N)
HB_CLK_P: J1.E36(HB21_P) J1.F37(HB20_P)
HB_N0: J1.E22(HB3_N) J1.F23(HB2_N)
HB_N1: J1.E25(HB5_N) J1.F26(HB4_N)
HB_N2: J1.E28(HB9_N) J1.F29(HB8_N)
HB_N3: J1.E31(HB13_N) J1.F32(HB12_N)
HB_N4: J1.E34(HB19_N) J1.F35(HB16_N)
HB_N5: J1.J22(HA22_N) J1.J25(HB1_N)
HB_N6: J1.J28(HB7_N) J1.J31(HB11_N)
HB_N7: J1.J34(HB15_N) J1.J37(HB18_N)
HB_P0: J1.E21(HB3_P) J1.F22(HB2_P)
HB_P1: J1.E24(HB5_P) J1.F25(HB4_P)
HB_P2: J1.E27(HB9_P) J1.F28(HB8_P)
HB_P3: J1.E30(HB13_P) J1.F31(HB12_P)
HB_P4: J1.E33(HB19_P) J1.F34(HB16_P)
HB_P5: J1.J21(HA22_P) J1.J24(HB1_P)
HB_P6: J1.J27(HB7_P) J1.J30(HB11_P)
HB_P7: J1.J33(HB15_P) J1.J36(HB18_P)
HOST_CLK_N: C63.2 J1.D9(LA01_N_CC)
HOST_CLK_P: C62.2 J1.D8(LA01_P_CC)
JTAG_TD: J1.D30(TDI) J1.D31(TDO)
LA_CLK_N: J1.G7(LA00_N_CC) U2.4(CLK0n)
LA_CLK_P: J1.G6(LA00_P_CC) U2.5(CLK0p)
LA_N0: J1.G10(LA03_N) J1.H8(LA02_N)
LA_N1: J1.C11(LA06_N) J1.H11(LA04_N)
LA_N2: J1.D12(LA05_N) J1.G13(LA08_N)
LA_N3: J1.C15(LA10_N) J1.H14(LA07_N)
LA_N4: J1.D15(LA09_N) J1.G16(LA12_N)
LA_N5: J1.C19(LA14_N) J1.H17(LA11_N)
LA_N6: J1.D18(LA13_N) J1.G19(LA16_N)
LA_N7: J1.C23(LA18_N_CC) J1.H20(LA15_N)
LA_N8: J1.D21(LA17_N_CC) J1.G22(LA20_N)
LA_N9: J1.G25(LA22_N) J1.H23(LA19_N)
LA_N10: J1.G28(LA25_N) J1.H26(LA21_N)
LA_N11: J1.C27(LA27_N) J1.D24(LA23_N)
LA_N12: J1.G31(LA29_N) J1.H29(LA24_N)
LA_N13: J1.D27(LA26_N) J1.G34(LA31_N)
LA_N14: J1.G37(LA33_N) J1.H32(LA28_N)
LA_N15: J1.H35(LA30_N) J1.H38(LA32_N)
LA_P0: J1.G9(LA03_P) J1.H7(LA02_P)
LA_P1: J1.C10(LA06_P) J1.H10(LA04_P)
LA_P2: J1.D11(LA05_P) J1.G12(LA08_P)
LA_P3: J1.C14(LA10_P) J1.H13(LA07_P)
LA_P4: J1.D14(LA09_P) J1.G15(LA12_P)
LA_P5: J1.C18(LA14_P) J1.H16(LA11_P)
LA_P6: J1.D17(LA13_P) J1.G18(LA16_P)
LA_P7: J1.C22(LA18_P_CC) J1.H19(LA15_P)
LA_P8: J1.D20(LA17_P_CC) J1.G21(LA20_P)
LA_P9: J1.G24(LA22_P) J1.H22(LA19_P)
LA_P10: J1.G27(LA25_P) J1.H25(LA21_P)
LA_P11: J1.C26(LA27_P) J1.D23(LA23_P)
LA_P12: J1.G30(LA29_P) J1.H28(LA24_P)
LA_P13: J1.D26(LA26_P) J1.G33(LA31_P)
LA_P14: J1.G36(LA33_P) J1.H31(LA28_P)
LA_P15: J1.H34(LA30_P) J1.H37(LA32_P)
OEA_0: R14.2 U2.12(OEA)
OEA_1: R20.2 U3.12(OEA)
OEB_0: R13.2 U2.13(OEB)
OEB_1: R17.2 U3.13(OEB)
PG_C2M: J1.D1(PG_C2M) R3.2
PG_M2C: J1.F1(PG_M2C) R4.2
REFCLK_N: C65.2 J1.L21(REFCLK_C2M_N) J1.L25(REFCLK_M2C_N)
REFCLK_P: C64.2 J1.L20(REFCLK_C2M_P) J1.L24(REFCLK_M2C_P)
SCL: J1.C30(SCL) R7.1 U1.6(SCL) Y1.8(SCL)
SDA: J1.C31(SDA) R8.1 U1.5(SDA) Y1.7(SDA)
SYNC_N: J1.L17(SYNC_C2M_N) J1.L29(SYNC_M2C_N)
SYNC_P: J1.L16(SYNC_C2M_P) J1.L28(SYNC_M2C_P)
TRAN_CLK_N: C78.2 U2.21(CLK5p)
TRAN_CLK_P: C73.2 U2.20(CLK5n)
VADJ: J1.E39(VADJ) J1.F40(VADJ) J1.G39(VADJ) J1.H40(VADJ) R1.1 R2.1
VIO_M2C: J1.J39(VIO_B_M2C) J1.K40(VIO_B_M2C) R1.2
VREF_0: C70.1 U2.17(VREF)
VREF_1: C88.1 U3.17(VREF)
VREF_M2C: J1.H1(VREF_A_M2C) J1.K1(VREF_B_M2C) R2.2
N11804301: C66.1 FB1.2 Y1.6(VCC)

Not connected (* = marked no-connect by the designer): J1 B40(RES0)* D29(TCK)* D33(TMS)* D34(TRST_L)* L1(RES1)* L32(RES2)* L33(RES3)*; U2 1(DIVA)* 9(NC1)* 16(NC0)* 24(DIVB)* 25(CLK4n)* 26(CLK4p)* 27(CLK3n)* 28(CLK3p)*; U3 1(DIVA)* 9(NC1)* 16(NC0)* 24(DIVB)*; Y1 1(NC)*

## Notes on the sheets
sheet 1
- REV
- DATE
- PAGES
- DESCRIPTION
- NOTES:
- 1.
- Project Drawing Numbers:
       Raw PCB
       Gerber Files
       PCB Design Files
       Assembly Drawing
       Fab Drawing
       Schematic Drawing
       PCB Film
       Bill of Materials
       Schematic Design Files
       Functional Specification
       PCB Layout Guidelines
       Assembly Rework
- 01
- 07/22/16
- All
- Preliminary
- 100-0330631-A1
  110-0330631-A1
  120-0330631-A1
  130-0330631-A1
  140-0330631-A1
  150-0330631-A1
  160-0330631-A1
  170-0330631-A1
  180-0330631-A1
  210-0330631-A1
  220-0330631-A1
  320-0330631-A1
- 2.
- The FMC+ pinout was based on v57d4-r1d0t-2016-Mar-17, table 5-1.
- 3.
- This board was designd for Stratix 10 SI Development kit rev A.
- FMC+ Loopback
- PAGE
- DESCRIPTION
- 1
- Title, Notes, Block Diagram, Rev. History
- 2
- FMC+ LA / HA / HB
- 3
- FMC+ DP
- DC Blocking Caps
- 4
- Clock Buffer
- FMC+ Connector
- Transceiver Signals
- LVDS or CMOS Signals
- Clock Signals
- Clock
  Buffer
- I2C Signals
- Serial EEPROM
sheet 2
- FMC+ LA / HA / HB
- LA[33:0]/HA[23:0]/HB[21:0] loopback are following the Altera Extended FMC Specification,
  which are backward compatible with FMC loopback card pinout.
- TX/RX direction are shown in text aside.
- LA_TX_P8
- HA_TX_CLK_P
- HA_TX_P2
- LA_TX_N8
- HA_TX_CLK_N
- HA_TX_N2
- LA_RX_P7
- HA_RX_CLK_P
- HA_RX_P2
- LA_TX_P0
- LA_RX_N7
- LA_TX_P9
- HA_RX_CLK_N
- HA_RX_N2
- HA_TX_P7
- LA_TX_N0
- LA_TX_N9
- HA_TX_N7
- LA_RX_P0
- LA_RX_P8
- HA_RX_P5
- HA_TX_P3
- LA_RX_N0
- LA_RX_N8
- HA_RX_N5
- HA_TX_N3
- LA_TX_N1
- LA_TX_P1
- LA_TX_N10
- LA_TX_P10
- HA_TX_N0
- HA_TX_P0
- HA_RX_N3
- HA_RX_P3
- LA_TX_P2
- LA_RX_P9
- HA_RX_P0
- LA_TX_N2
- LA_RX_N9
- HA_RX_N0
- LA_RX_P1
- LA_TX_P11
- HA_RX_P7
- LA_RX_N1
- LA_TX_N11
- HA_RX_N7
- LA_TX_P3
- LA_TX_P12
- HA_TX_P6
- HA_TX_P4
- LA_TX_N3
- LA_TX_N12
- HA_TX_N6
- HA_TX_N4
- LA_RX_P2
- LA_RX_P10
- HA_TX_P1
- HA_RX_P4
- LA_RX_N2
- LA_RX_N10
- HA_TX_N1
- HA_RX_N4
- LA_TX_P4
- LA_TX_P13
- HA_RX_P1
- LA_TX_N4
- LA_TX_N13
- HA_RX_N1
- LA_RX_N3
- LA_RX_P3
- LA_RX_N11
- LA_RX_P11
- HB_RX_N5
- HB_RX_P5
- LA_TX_P5
- LA_TX_P14
- HA_RX_P6
- LA_TX_N5
- LA_TX_N14
- HA_RX_N6
- LA_RX_P4
- LA_RX_P12
- LA_RX_N4
- LA_RX_N12
- LA_TX_N6
- LA_TX_P6
- LA_TX_N15
- LA_TX_P15
- LA_RX_P5
- LA_RX_P13
- LA_RX_N5
- LA_RX_N13
- LA_TX_P7
- LA_RX_P15
- DP[10:15] were defined as XCVRs
  in Altera Extended FMC Specification.
  Replace Caps with 0 ohm resistors
  to test LVDS or single ended systems.
- LA_TX_N7
- LA_RX_N15
- LA_RX_N6
- LA_RX_P6
- LA_RX_N14
- LA_RX_P14
- HB_TX_P6
- HB_TX_N6
- HB_TX_P5
- HB_TX_P3
- HB_TX_N5
- HB_TX_N3
- HB_TX_N0
- HB_TX_P0
- HB_RX_N3
- HB_RX_P3
- HB_RX_P0
- HB_RX_N0
- HB_TX_P1
- HB_RX_P7
- HB_TX_N1
- HB_RX_N7
- HB_RX_N1
- HB_RX_P1
- HB_TX_N4
- HB_TX_P4
- HB_RX_P6
- HB_TX_P7
- HB_RX_N6
- HB_TX_N7
- HB_TX_N2
- HB_TX_P2
- HB_RX_N4
- HB_RX_P4
- HB_RX_P2
- HB_TX_CLK_P
- HB_RX_N2
- HB_TX_CLK_N
- HB_RX_CLK_P
- HB_RX_CLK_N
- HA_TX_P5
- HA_TX_N5
sheet 3
- FMC+ DP
sheet 4
- Clock Buffer
- Silicon Labs Oscillator
  factory program
  @ 644.53125 MHz
  ADDR - 55h
- When CLKSEL is high, CLK1 is selected. (DEFAULT)
  When CLKSEL is low, CLK0 is selected.
